VERSION 5.7 ;
  NOWIREEXTENSIONATPIN ON ;
  DIVIDERCHAR "/" ;
  BUSBITCHARS "[]" ;
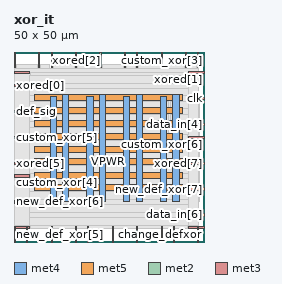
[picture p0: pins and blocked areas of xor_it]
MACRO xor_it
  CLASS BLOCK ;
  FOREIGN xor_it ;
  ORIGIN 0.000 0.000 ;
  SIZE 50.000 BY 50.000 ;
  PIN VGND
    DIRECTION INOUT ;
    USE GROUND ;
    PORT
      LAYER met4 ;
        RECT 12.850 10.640 14.450 38.760 ;
    END
    PORT
      LAYER met4 ;
        RECT 22.510 10.640 24.110 38.760 ;
    END
    PORT
      LAYER met4 ;
        RECT 32.170 10.640 33.770 38.760 ;
    END
    PORT
      LAYER met4 ;
        RECT 41.830 10.640 43.430 38.760 ;
    END
    PORT
      LAYER met5 ;
        RECT 5.280 16.775 44.400 18.375 ;
    END
    PORT
      LAYER met5 ;
        RECT 5.280 23.570 44.400 25.170 ;
    END
    PORT
      LAYER met5 ;
        RECT 5.280 30.365 44.400 31.965 ;
    END
    PORT
      LAYER met5 ;
        RECT 5.280 37.160 44.400 38.760 ;
    END
  END VGND
  PIN VPWR
    DIRECTION INOUT ;
    USE POWER ;
    PORT
      LAYER met4 ;
        RECT 9.550 10.640 11.150 38.320 ;
    END
    PORT
      LAYER met4 ;
        RECT 19.210 10.640 20.810 38.320 ;
    END
    PORT
      LAYER met4 ;
        RECT 28.870 10.640 30.470 38.320 ;
    END
    PORT
      LAYER met4 ;
        RECT 38.530 10.640 40.130 38.320 ;
    END
    PORT
      LAYER met5 ;
        RECT 5.280 13.475 44.400 15.075 ;
    END
    PORT
      LAYER met5 ;
        RECT 5.280 20.270 44.400 21.870 ;
    END
    PORT
      LAYER met5 ;
        RECT 5.280 27.065 44.400 28.665 ;
    END
    PORT
      LAYER met5 ;
        RECT 5.280 33.860 44.400 35.460 ;
    END
  END VPWR
  PIN change_defxor
    DIRECTION INPUT ;
    USE SIGNAL ;
    ANTENNAGATEAREA 0.196500 ;
    PORT
      LAYER met2 ;
        RECT 41.950 0.000 42.230 4.000 ;
    END
  END change_defxor
  PIN clk
    DIRECTION INPUT ;
    USE SIGNAL ;
    ANTENNAGATEAREA 0.852000 ;
    PORT
      LAYER met3 ;
        RECT 46.000 37.440 50.000 38.040 ;
    END
  END clk
  PIN custom_xor[0]
    DIRECTION INPUT ;
    USE SIGNAL ;
    ANTENNAGATEAREA 0.196500 ;
    PORT
      LAYER met2 ;
        RECT 9.750 46.000 10.030 50.000 ;
    END
  END custom_xor[0]
  PIN custom_xor[1]
    DIRECTION INPUT ;
    USE SIGNAL ;
    ANTENNAGATEAREA 0.196500 ;
    PORT
      LAYER met2 ;
        RECT 25.850 0.000 26.130 4.000 ;
    END
  END custom_xor[1]
  PIN custom_xor[2]
    DIRECTION INPUT ;
    USE SIGNAL ;
    ANTENNAGATEAREA 0.196500 ;
    PORT
      LAYER met2 ;
        RECT 16.190 0.000 16.470 4.000 ;
    END
  END custom_xor[2]
  PIN custom_xor[3]
    DIRECTION INPUT ;
    USE SIGNAL ;
    ANTENNAGATEAREA 0.196500 ;
    PORT
      LAYER met2 ;
        RECT 38.730 46.000 39.010 50.000 ;
    END
  END custom_xor[3]
  PIN custom_xor[4]
    DIRECTION INPUT ;
    USE SIGNAL ;
    ANTENNAGATEAREA 0.196500 ;
    PORT
      LAYER met3 ;
        RECT 0.000 17.040 4.000 17.640 ;
    END
  END custom_xor[4]
  PIN custom_xor[5]
    DIRECTION INPUT ;
    USE SIGNAL ;
    ANTENNAGATEAREA 0.196500 ;
    PORT
      LAYER met3 ;
        RECT 0.000 27.240 4.000 27.840 ;
    END
  END custom_xor[5]
  PIN custom_xor[6]
    DIRECTION INPUT ;
    USE SIGNAL ;
    ANTENNAGATEAREA 0.196500 ;
    PORT
      LAYER met3 ;
        RECT 46.000 27.240 50.000 27.840 ;
    END
  END custom_xor[6]
  PIN custom_xor[7]
    DIRECTION INPUT ;
    USE SIGNAL ;
    ANTENNAGATEAREA 0.196500 ;
    PORT
      LAYER met2 ;
        RECT 48.390 46.000 48.670 50.000 ;
    END
  END custom_xor[7]
  PIN data_in[0]
    DIRECTION INPUT ;
    USE SIGNAL ;
    ANTENNAGATEAREA 0.196500 ;
    PORT
      LAYER met2 ;
        RECT 29.070 46.000 29.350 50.000 ;
    END
  END data_in[0]
  PIN data_in[1]
    DIRECTION INPUT ;
    USE SIGNAL ;
    ANTENNAGATEAREA 0.196500 ;
    PORT
      LAYER met3 ;
        RECT 0.000 44.240 4.000 44.840 ;
    END
  END data_in[1]
  PIN data_in[2]
    DIRECTION INPUT ;
    USE SIGNAL ;
    ANTENNAGATEAREA 0.196500 ;
    PORT
      LAYER met2 ;
        RECT 48.390 0.000 48.670 4.000 ;
    END
  END data_in[2]
  PIN data_in[3]
    DIRECTION INPUT ;
    USE SIGNAL ;
    ANTENNAGATEAREA 0.196500 ;
    PORT
      LAYER met3 ;
        RECT 0.000 3.440 4.000 4.040 ;
    END
  END data_in[3]
  PIN data_in[4]
    DIRECTION INPUT ;
    USE SIGNAL ;
    ANTENNAGATEAREA 0.196500 ;
    PORT
      LAYER met3 ;
        RECT 46.000 30.640 50.000 31.240 ;
    END
  END data_in[4]
  PIN data_in[5]
    DIRECTION INPUT ;
    USE SIGNAL ;
    ANTENNAGATEAREA 0.196500 ;
    PORT
      LAYER met2 ;
        RECT 0.090 0.000 0.370 4.000 ;
    END
  END data_in[5]
  PIN data_in[6]
    DIRECTION INPUT ;
    USE SIGNAL ;
    ANTENNAGATEAREA 0.196500 ;
    PORT
      LAYER met3 ;
        RECT 46.000 6.840 50.000 7.440 ;
    END
  END data_in[6]
  PIN data_in[7]
    DIRECTION INPUT ;
    USE SIGNAL ;
    ANTENNAGATEAREA 0.196500 ;
    PORT
      LAYER met2 ;
        RECT 32.290 46.000 32.570 50.000 ;
    END
  END data_in[7]
  PIN def_sig
    DIRECTION INPUT ;
    USE SIGNAL ;
    ANTENNAGATEAREA 0.213000 ;
    PORT
      LAYER met3 ;
        RECT 0.000 34.040 4.000 34.640 ;
    END
  END def_sig
  PIN new_def_xor[0]
    DIRECTION INPUT ;
    USE SIGNAL ;
    ANTENNAGATEAREA 0.196500 ;
    PORT
      LAYER met2 ;
        RECT 6.530 46.000 6.810 50.000 ;
    END
  END new_def_xor[0]
  PIN new_def_xor[1]
    DIRECTION INPUT ;
    USE SIGNAL ;
    ANTENNAGATEAREA 0.196500 ;
    PORT
      LAYER met2 ;
        RECT 38.730 0.000 39.010 4.000 ;
    END
  END new_def_xor[1]
  PIN new_def_xor[2]
    DIRECTION INPUT ;
    USE SIGNAL ;
    ANTENNAGATEAREA 0.196500 ;
    PORT
      LAYER met2 ;
        RECT 45.170 46.000 45.450 50.000 ;
    END
  END new_def_xor[2]
  PIN new_def_xor[3]
    DIRECTION INPUT ;
    USE SIGNAL ;
    ANTENNAGATEAREA 0.196500 ;
    PORT
      LAYER met3 ;
        RECT 46.000 3.440 50.000 4.040 ;
    END
  END new_def_xor[3]
  PIN new_def_xor[4]
    DIRECTION INPUT ;
    USE SIGNAL ;
    ANTENNAGATEAREA 0.196500 ;
    PORT
      LAYER met2 ;
        RECT 3.310 0.000 3.590 4.000 ;
    END
  END new_def_xor[4]
  PIN new_def_xor[5]
    DIRECTION INPUT ;
    USE SIGNAL ;
    ANTENNAGATEAREA 0.196500 ;
    PORT
      LAYER met2 ;
        RECT 9.750 0.000 10.030 4.000 ;
    END
  END new_def_xor[5]
  PIN new_def_xor[6]
    DIRECTION INPUT ;
    USE SIGNAL ;
    ANTENNAGATEAREA 0.196500 ;
    PORT
      LAYER met3 ;
        RECT 0.000 10.240 4.000 10.840 ;
    END
  END new_def_xor[6]
  PIN new_def_xor[7]
    DIRECTION INPUT ;
    USE SIGNAL ;
    ANTENNAGATEAREA 0.196500 ;
    PORT
      LAYER met3 ;
        RECT 46.000 13.640 50.000 14.240 ;
    END
  END new_def_xor[7]
  PIN rst
    DIRECTION INPUT ;
    USE SIGNAL ;
    ANTENNAGATEAREA 0.213000 ;
    PORT
      LAYER met2 ;
        RECT 19.410 0.000 19.690 4.000 ;
    END
  END rst
  PIN xored[0]
    DIRECTION OUTPUT TRISTATE ;
    USE SIGNAL ;
    ANTENNADIFFAREA 0.795200 ;
    PORT
      LAYER met3 ;
        RECT 0.000 40.840 4.000 41.440 ;
    END
  END xored[0]
  PIN xored[1]
    DIRECTION OUTPUT TRISTATE ;
    USE SIGNAL ;
    ANTENNADIFFAREA 0.795200 ;
    PORT
      LAYER met3 ;
        RECT 46.000 44.240 50.000 44.840 ;
    END
  END xored[1]
  PIN xored[2]
    DIRECTION OUTPUT TRISTATE ;
    USE SIGNAL ;
    ANTENNADIFFAREA 0.795200 ;
    PORT
      LAYER met2 ;
        RECT 16.190 46.000 16.470 50.000 ;
    END
  END xored[2]
  PIN xored[3]
    DIRECTION OUTPUT TRISTATE ;
    USE SIGNAL ;
    ANTENNADIFFAREA 0.445500 ;
    PORT
      LAYER met2 ;
        RECT 22.630 46.000 22.910 50.000 ;
    END
  END xored[3]
  PIN xored[4]
    DIRECTION OUTPUT TRISTATE ;
    USE SIGNAL ;
    ANTENNADIFFAREA 0.795200 ;
    PORT
      LAYER met2 ;
        RECT 32.290 0.000 32.570 4.000 ;
    END
  END xored[4]
  PIN xored[5]
    DIRECTION OUTPUT TRISTATE ;
    USE SIGNAL ;
    ANTENNADIFFAREA 0.795200 ;
    PORT
      LAYER met3 ;
        RECT 0.000 20.440 4.000 21.040 ;
    END
  END xored[5]
  PIN xored[6]
    DIRECTION OUTPUT TRISTATE ;
    USE SIGNAL ;
    ANTENNADIFFAREA 0.795200 ;
    PORT
      LAYER met2 ;
        RECT 0.090 46.000 0.370 50.000 ;
    END
  END xored[6]
  PIN xored[7]
    DIRECTION OUTPUT TRISTATE ;
    USE SIGNAL ;
    ANTENNADIFFAREA 0.795200 ;
    PORT
      LAYER met3 ;
        RECT 46.000 20.440 50.000 21.040 ;
    END
  END xored[7]
  OBS
      LAYER li1 ;
        RECT 5.520 10.795 44.160 38.165 ;
      LAYER met1 ;
        RECT 0.070 10.640 48.690 38.320 ;
      LAYER met2 ;
        RECT 0.650 45.720 6.250 46.650 ;
        RECT 7.090 45.720 9.470 46.650 ;
        RECT 10.310 45.720 15.910 46.650 ;
        RECT 16.750 45.720 22.350 46.650 ;
        RECT 23.190 45.720 28.790 46.650 ;
        RECT 29.630 45.720 32.010 46.650 ;
        RECT 32.850 45.720 38.450 46.650 ;
        RECT 39.290 45.720 44.890 46.650 ;
        RECT 45.730 45.720 48.110 46.650 ;
        RECT 0.100 4.280 48.660 45.720 ;
        RECT 0.650 3.555 3.030 4.280 ;
        RECT 3.870 3.555 9.470 4.280 ;
        RECT 10.310 3.555 15.910 4.280 ;
        RECT 16.750 3.555 19.130 4.280 ;
        RECT 19.970 3.555 25.570 4.280 ;
        RECT 26.410 3.555 32.010 4.280 ;
        RECT 32.850 3.555 38.450 4.280 ;
        RECT 39.290 3.555 41.670 4.280 ;
        RECT 42.510 3.555 48.110 4.280 ;
      LAYER met3 ;
        RECT 4.400 43.840 45.600 44.705 ;
        RECT 4.000 41.840 46.000 43.840 ;
        RECT 4.400 40.440 46.000 41.840 ;
        RECT 4.000 38.440 46.000 40.440 ;
        RECT 4.000 37.040 45.600 38.440 ;
        RECT 4.000 35.040 46.000 37.040 ;
        RECT 4.400 33.640 46.000 35.040 ;
        RECT 4.000 31.640 46.000 33.640 ;
        RECT 4.000 30.240 45.600 31.640 ;
        RECT 4.000 28.240 46.000 30.240 ;
        RECT 4.400 26.840 45.600 28.240 ;
        RECT 4.000 21.440 46.000 26.840 ;
        RECT 4.400 20.040 45.600 21.440 ;
        RECT 4.000 18.040 46.000 20.040 ;
        RECT 4.400 16.640 46.000 18.040 ;
        RECT 4.000 14.640 46.000 16.640 ;
        RECT 4.000 13.240 45.600 14.640 ;
        RECT 4.000 11.240 46.000 13.240 ;
        RECT 4.400 9.840 46.000 11.240 ;
        RECT 4.000 7.840 46.000 9.840 ;
        RECT 4.000 6.440 45.600 7.840 ;
        RECT 4.000 4.440 46.000 6.440 ;
        RECT 4.400 3.575 45.600 4.440 ;
      LAYER met4 ;
        RECT 40.775 27.375 41.105 37.225 ;
  END
END xor_it
END LIBRARY

